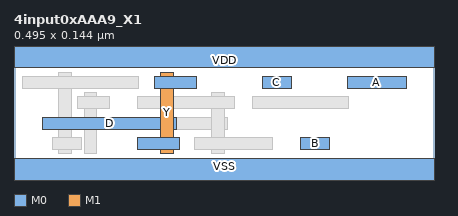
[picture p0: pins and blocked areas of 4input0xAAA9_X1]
MACRO 4input0xAAA9_X1
  CLASS CORE ;
  ORIGIN 0 0 ;
  FOREIGN 4input0xAAA9_X1 0 0 ;
  SIZE 0.4950 BY 0.1440 ;
  SYMMETRY X Y ;
  SITE coresite ;
  PIN A
    DIRECTION INPUT ;
    USE SIGNAL ;
    PORT
      LAYER M0 ;
        RECT 0.3930 0.1010 0.4620 0.1150 ;
    END
  END A
  PIN B
    DIRECTION INPUT ;
    USE SIGNAL ;
    PORT
      LAYER M0 ;
        RECT 0.3375 0.0290 0.3720 0.0430 ;
    END
  END B
  PIN C
    DIRECTION INPUT ;
    USE SIGNAL ;
    PORT
      LAYER M0 ;
        RECT 0.2925 0.1010 0.3270 0.1150 ;
    END
  END C
  PIN D
    DIRECTION INPUT ;
    USE SIGNAL ;
    PORT
      LAYER M0 ;
        RECT 0.0330 0.0530 0.1920 0.0670 ;
    END
  END D
  PIN Y
    DIRECTION OUTPUT ;
    USE SIGNAL ;
    PORT
      LAYER M1 ;
        RECT 0.1725 0.0240 0.1875 0.1200 ;
      LAYER M0 ;
        RECT 0.1650 0.1010 0.2145 0.1150 ;
        RECT 0.1455 0.0290 0.1950 0.0430 ;
    END
  END Y
  PIN VDD
    DIRECTION INOUT ;
    USE POWER ;
    SHAPE ABUTMENT ;
    PORT
      LAYER M0 ;
        RECT 0.0000 0.1260 0.4950 0.1620 ;
    END
  END VDD
  PIN VSS
    DIRECTION INOUT ;
    USE GROUND ;
    SHAPE ABUTMENT ;
    PORT
      LAYER M0 ;
        RECT 0.0000 -0.0180 0.4950 0.0180 ;
    END
  END VSS
  OBS
    LAYER M2 ;
      RECT 0.0780 0.0530 0.2520 0.0670 ;
    LAYER V1 ;
      RECT 0.0830 0.0530 0.0970 0.0670 ;
      RECT 0.2330 0.0530 0.2470 0.0670 ;
    LAYER M1 ;
      RECT 0.0825 0.0240 0.0975 0.0960 ;
      RECT 0.2325 0.0240 0.2475 0.0960 ;
      RECT 0.0525 0.0240 0.0675 0.1200 ;
    LAYER V0 ;
      RECT 0.0830 0.0770 0.0970 0.0910 ;
      RECT 0.2330 0.0290 0.2470 0.0430 ;
      RECT 0.0530 0.1010 0.0670 0.1150 ;
      RECT 0.0530 0.0290 0.0670 0.0430 ;
      RECT 0.1730 0.1010 0.1870 0.1150 ;
      RECT 0.1730 0.0290 0.1870 0.0430 ;
    LAYER M0 ;
      RECT 0.0450 0.0290 0.0795 0.0430 ;
      RECT 0.2130 0.0290 0.3045 0.0430 ;
      RECT 0.0750 0.0770 0.1125 0.0910 ;
      RECT 0.1455 0.0770 0.2595 0.0910 ;
      RECT 0.2805 0.0770 0.3945 0.0910 ;
      RECT 0.0105 0.1010 0.1470 0.1150 ;
  END
END 4input0xAAA9_X1
